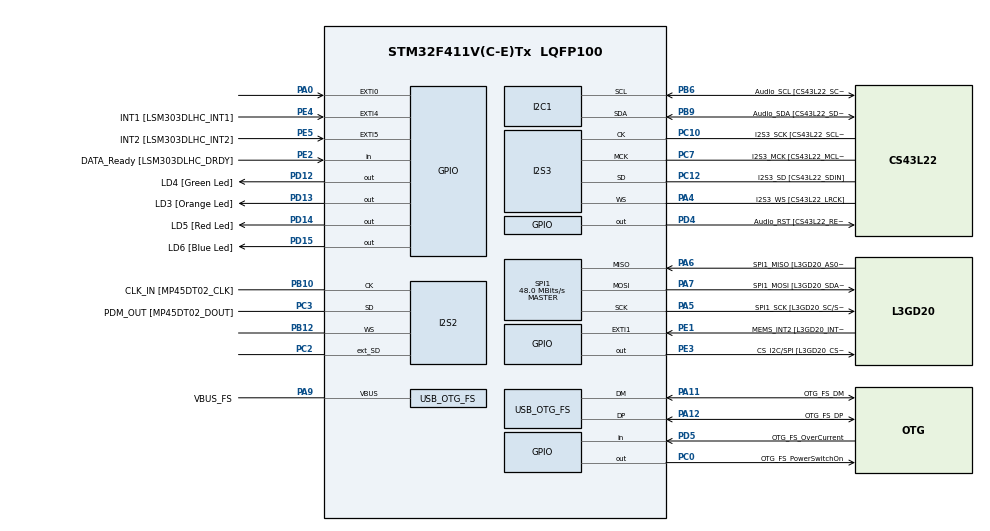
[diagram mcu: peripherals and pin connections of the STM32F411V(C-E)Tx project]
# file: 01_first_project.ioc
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Mcu.Family=STM32F4
PC3.Mode=Full_Duplex_Master
PD12.GPIO_Label=LD4 [Green Led]
PA6.Mode=Full_Duplex_Master
RCC.CortexFreq_Value=96000000
PC10.GPIO_PuPd=GPIO_NOPULL
SPI1.VirtualType=VM_MASTER
PB6.GPIO_Mode=GPIO_MODE_AF_OD
PB10.Mode=Full_Duplex_Master
PD15.GPIO_Speed=GPIO_SPEED_FREQ_LOW
PC10.Signal=I2S3_CK
PC12.Signal=I2S3_SD
PA14.GPIO_Label=SWCLK
PC0.GPIO_Label=OTG_FS_PowerSwitchOn
PA11.Mode=Host_Only
PA6.GPIO_Label=SPI1_MISO [L3GD20_AS0/SDO]
PB6.GPIO_Label=Audio_SCL [CS43L22_SCL]
PC10.GPIO_Speed=GPIO_SPEED_FREQ_LOW
PC15-OSC32_OUT.GPIO_Label=PC15-OSC32_OUT
RCC.SYSCLKSource=RCC_SYSCLKSOURCE_PLLCLK
ProjectManager.StackSize=0x400
PD13.Signal=GPIO_Output
PD14.GPIO_Speed=GPIO_SPEED_FREQ_LOW
PA12.Signal=USB_OTG_FS_DP
PH0\ -\ OSC_IN.Signal=RCC_OSC_IN
PA4.Mode=Half_Duplex_Master
SPI1.Direction=SPI_DIRECTION_2LINES
RCC.HCLKFreq_Value=96000000
PD4.Signal=GPIO_Output
RCC.APB2TimFreq_Value=96000000
PB6.Signal=I2C1_SCL
PC7.Signal=I2S3_MCK
PB6.Mode=I2C
SPI1.CalculateBaudRate=48.0 MBits/s
PC3.Signal=I2S2_SD
PE5.Signal=GPXTI5
PE1.Signal=GPXTI1
USB_HOST0.BSP.ip=GPIO
RCC.AHBFreq_Value=96000000
RCC.HSE_VALUE=8000000
USB_OTG_FS.phy_itface=HCD_PHY_EMBEDDED
PA4.GPIO_PuPd=GPIO_NOPULL
PA4.GPIO_Speed=GPIO_SPEED_FREQ_LOW
I2S3.ErrorAudioFreq=-6.99 %
PC14-OSC32_IN.Mode=LSE-External-Oscillator
PA14.Mode=Serial_Wire
PA10.GPIO_Label=OTG_FS_ID
PE4.GPIO_Label=INT1 [LSM303DLHC_INT1]
PC7.GPIO_Mode=GPIO_MODE_AF_PP
PE2.Signal=GPIO_Input
PD14.GPIO_PuPd=GPIO_NOPULL
USB_HOST0.BSP.i2creg=0
PE4.Signal=GPXTI4
USB_HOST0.BSP.i2caddr=0
PD13.GPIO_Label=LD3 [Orange Led]
Mcu.Package=LQFP100
PB9.Signal=I2C1_SDA
PA6.Signal=SPI1_MISO
PB12.Mode=Full_Duplex_Master
PD12.Signal=GPIO_Output
PD5.GPIO_Label=OTG_FS_OverCurrent
NVIC.OTG_FS_IRQn=true\:0\:0\:false\:false\:true\:true\:true
PD15.GPIO_PuPd=GPIO_NOPULL
PA10.Signal=USB_OTG_FS_ID
PB9.GPIO_PuPd=GPIO_NOPULL
USB_OTG_FS.VirtualMode=Host_Only
USB_HOST0.BSP.name=Drive_VBUS_FS
PB9.GPIO_Speed=GPIO_SPEED_FREQ_LOW
RCC.APB1TimFreq_Value=96000000
PC14-OSC32_IN.GPIO_Label=PC14-OSC32_IN
PC12.GPIO_PuPd=GPIO_NOPULL
SPI1.BaudRatePrescaler=SPI_BAUDRATEPRESCALER_2
PA4.GPIO_Label=I2S3_WS [CS43L22_LRCK]
PE2.GPIO_Label=DATA_Ready [LSM303DLHC_DRDY]
PD15.Signal=GPIO_Output
PC0.PinState=GPIO_PIN_SET
PA5.Mode=Full_Duplex_Master
PB3.GPIO_Label=SWO
PC15-OSC32_OUT.Mode=LSE-External-Oscillator
I2S2.AudioFreq=I2S_AUDIOFREQ_96K
I2S3.FullDuplexMode=I2S_FULLDUPLEXMODE_DISABLE
PD12.GPIO_Speed=GPIO_SPEED_FREQ_LOW
PD15.GPIO_Label=LD6 [Blue Led]
PA7.Mode=Full_Duplex_Master
I2S2.Instance=SPI$Index
PB9.GPIO_Label=Audio_SDA [CS43L22_SDA]
PC10.GPIO_Label=I2S3_SCK [CS43L22_SCLK]
PA9.GPIO_Label=VBUS_FS
PB6.GPIO_PuPd=GPIO_NOPULL
PH1\ -\ OSC_OUT.Mode=HSE-External-Clock-Source
USB_HOST0.BSP.solution=PC0
PC2.Signal=I2S2_ext_SD
PC10.Mode=Half_Duplex_Master
USB_HOST.BSP.number=1
PE4.GPIO_ModeDefaultEXTI=GPIO_MODE_EVT_RISING
PA11.GPIO_Label=OTG_FS_DM
PC2.Mode=Full_Duplex_Master
PD5.Signal=GPIO_Input
PC0.Signal=GPIO_Output
PE1.GPIO_ModeDefaultEXTI=GPIO_MODE_EVT_RISING
RCC.APB1CLKDivider=RCC_HCLK_DIV2
PC14-OSC32_IN.Signal=RCC_OSC32_IN
PA0-WKUP.GPIO_ModeDefaultEXTI=GPIO_MODE_EVT_RISING
PA12.GPIO_Label=OTG_FS_DP
PA0-WKUP.Signal=GPXTI0
USB_HOST0.BSP.STBoard=false
PA13.Signal=SYS_JTMS-SWDIO
PC10.GPIO_Mode=GPIO_MODE_AF_PP
PA9.Mode=Activate_VBUS
PH0\ -\ OSC_IN.Mode=HSE-External-Clock-Source
ProjectManager.TargetToolchain=STM32CubeIDE
PE5.GPIO_ModeDefaultEXTI=GPIO_MODE_EVT_RISING
PB10.GPIO_Label=CLK_IN [MP45DT02_CLK]
PB9.Mode=I2C
PA9.Signal=USB_OTG_FS_VBUS
I2S2.VirtualMode=I2S_MODE_MASTER
I2S3.VirtualMode=I2S_MODE_MASTER
PC7.GPIO_PuPd=GPIO_NOPULL
PC15-OSC32_OUT.Signal=RCC_OSC32_OUT
PB10.Signal=I2S2_CK
PA5.Signal=SPI1_SCK
I2S3.AudioFreq=I2S_AUDIOFREQ_96K
PC12.Mode=Half_Duplex_Master
PH1\ -\ OSC_OUT.Signal=RCC_OSC_OUT
board=STM32F411E-DISCO
PD13.GPIO_Speed=GPIO_SPEED_FREQ_LOW
PC7.GPIO_Speed=GPIO_SPEED_FREQ_LOW
RCC.VCOOutputFreq_Value=192000000
PE1.GPIO_Label=MEMS_INT2 [L3GD20_INT2]
USB_HOST.VirtualModeFS=Cdc
PB9.GPIO_Mode=GPIO_MODE_AF_OD
PA4.GPIO_Mode=GPIO_MODE_AF_PP
RCC.APB2Freq_Value=96000000
USB_HOST0.BSP.api=Unknown
SPI1.Mode=SPI_MODE_MASTER
PD4.GPIO_Label=Audio_RST [CS43L22_RESET]
PD13.GPIO_PuPd=GPIO_NOPULL
PD14.GPIO_Label=LD5 [Red Led]
PA13.Mode=Serial_Wire
Mcu.Name=STM32F411V(C-E)Tx
PA13.GPIO_Label=SWDIO
I2S2.FullDuplexMode=I2S_FULLDUPLEXMODE_ENABLE
PC7.GPIO_Label=I2S3_MCK [CS43L22_MCLK]
PD14.Signal=GPIO_Output
PH1\ -\ OSC_OUT.GPIO_Label=PH1-OSC_OUT
RCC.48MHZClocksFreq_Value=48000000
PB3.Signal=SYS_JTDO-SWO
PA4.Signal=I2S3_WS
RCC.SYSCLKFreq_VALUE=96000000
PC12.GPIO_Mode=GPIO_MODE_AF_PP
PA7.GPIO_Label=SPI1_MOSI [L3GD20_SDA/SDI/SDO]
PA12.Mode=Host_Only
PA5.GPIO_Label=SPI1_SCK [L3GD20_SC/SPC]
I2S2.ErrorAudioFreq=0.15 %
VP_USB_HOST_VS_USB_HOST_CDC_FS.Mode=CDC_FS
PE5.GPIO_Label=INT2 [LSM303DLHC_INT2]
PC12.GPIO_Label=I2S3_SD [CS43L22_SDIN]
PA11.Signal=USB_OTG_FS_DM
PA14.Signal=SYS_JTCK-SWCLK
ProjectManager.HeapSize=0x200
RCC.HSI_VALUE=16000000
USB_HOST.USBH_HandleTypeDef=hUsbHostFS
NVIC.PriorityGroup=NVIC_PRIORITYGROUP_0
I2S3.RealAudioFreq=89.285 KHz
RCC.PLLM=4
RCC.PLLN=96
PE3.Signal=GPIO_Output
PE3.GPIO_Label=CS_I2C/SPI [L3GD20_CS_I2C/SPI]
PC3.GPIO_Label=PDM_OUT [MP45DT02_DOUT]
PH0\ -\ OSC_IN.GPIO_Label=PH0-OSC_IN
I2S3.Instance=SPI$Index
PC7.Mode=Master_Clock_Activated
PB6.GPIO_Speed=GPIO_SPEED_FREQ_LOW
RCC.APB1Freq_Value=48000000
PC12.GPIO_Speed=GPIO_SPEED_FREQ_LOW
I2S2.RealAudioFreq=96.153 KHz
USB_HOST0.BSP.mode=Output
RCC.PLLI2SN=200
PB12.Signal=I2S2_WS
PD12.GPIO_PuPd=GPIO_NOPULL
RCC.PLLI2SM=5
PA7.Signal=SPI1_MOSI
USB_HOST0.BSP.instance=PC0

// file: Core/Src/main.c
/* USER CODE BEGIN Header */
/**
  ******************************************************************************
  * @file           : main.c
  * @brief          : Main program body
  ******************************************************************************
  * @attention
  *
  * <h2><center>&copy; Copyright (c) 2020 STMicroelectronics.
  * All rights reserved.</center></h2>
  *
  * This software component is licensed by ST under Ultimate Liberty license
  * SLA0044, the "License"; You may not use this file except in compliance with
  * the License. You may obtain a copy of the License at:
  *                             www.st.com/SLA0044
  *
  ******************************************************************************
  */
/* USER CODE END Header */
#include "main.h"
#include "i2c.h"
#include "i2s.h"
#include "spi.h"
#include "usb_host.h"
#include "gpio.h"

void SystemClock_Config(void);
void MX_USB_HOST_Process(void);

int main(void)
{

  /* MCU Configuration--------------------------------------------------------*/

  /* Reset of all peripherals, Initializes the Flash interface and the Systick. */
  HAL_Init();

  /* Configure the system clock */
  SystemClock_Config();

  /* Initialize all configured peripherals */
  MX_GPIO_Init();
  MX_I2C1_Init();
  MX_I2S2_Init();
  MX_I2S3_Init();
  MX_SPI1_Init();
  MX_USB_HOST_Init();

  /* Infinite loop */
  while (1)
  {
    MX_USB_HOST_Process();

  }
}

void SystemClock_Config(void)
{
  RCC_OscInitTypeDef RCC_OscInitStruct = {0};
  RCC_ClkInitTypeDef RCC_ClkInitStruct = {0};
  RCC_PeriphCLKInitTypeDef PeriphClkInitStruct = {0};

  /** Configure the main internal regulator output voltage
  */
  __HAL_RCC_PWR_CLK_ENABLE();
  __HAL_PWR_VOLTAGESCALING_CONFIG(PWR_REGULATOR_VOLTAGE_SCALE1);
  /** Initializes the RCC Oscillators according to the specified parameters
  * in the RCC_OscInitTypeDef structure.
  */
  RCC_OscInitStruct.OscillatorType = RCC_OSCILLATORTYPE_HSE;
  RCC_OscInitStruct.HSEState = RCC_HSE_BYPASS;
  RCC_OscInitStruct.PLL.PLLState = RCC_PLL_ON;
  RCC_OscInitStruct.PLL.PLLSource = RCC_PLLSOURCE_HSE;
  RCC_OscInitStruct.PLL.PLLM = 4;
  RCC_OscInitStruct.PLL.PLLN = 192;
  RCC_OscInitStruct.PLL.PLLP = RCC_PLLP_DIV4;
  RCC_OscInitStruct.PLL.PLLQ = 8;
  if (HAL_RCC_OscConfig(&RCC_OscInitStruct) != HAL_OK)
  {
    Error_Handler();
  }
  /** Initializes the CPU, AHB and APB buses clocks
  */
  RCC_ClkInitStruct.ClockType = RCC_CLOCKTYPE_HCLK|RCC_CLOCKTYPE_SYSCLK
                              |RCC_CLOCKTYPE_PCLK1|RCC_CLOCKTYPE_PCLK2;
  RCC_ClkInitStruct.SYSCLKSource = RCC_SYSCLKSOURCE_PLLCLK;
  RCC_ClkInitStruct.AHBCLKDivider = RCC_SYSCLK_DIV1;
  RCC_ClkInitStruct.APB1CLKDivider = RCC_HCLK_DIV4;
  RCC_ClkInitStruct.APB2CLKDivider = RCC_HCLK_DIV1;

  if (HAL_RCC_ClockConfig(&RCC_ClkInitStruct, FLASH_LATENCY_3) != HAL_OK)
  {
    Error_Handler();
  }
  PeriphClkInitStruct.PeriphClockSelection = RCC_PERIPHCLK_I2S;
  PeriphClkInitStruct.PLLI2S.PLLI2SN = 200;
  PeriphClkInitStruct.PLLI2S.PLLI2SM = 5;
  PeriphClkInitStruct.PLLI2S.PLLI2SR = 2;
  if (HAL_RCCEx_PeriphCLKConfig(&PeriphClkInitStruct) != HAL_OK)
  {
    Error_Handler();
  }
}

void Error_Handler(void)
{
  __disable_irq();
  while (1)
  {
  }
}

/************************ (C) COPYRIGHT STMicroelectronics *****END OF FILE****/
